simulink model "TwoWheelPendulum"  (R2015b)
settings: Solver=ode45  StartTime=0.0  StopTime=200.0  RelTol=1e-3
PreLoadFcn:
  | UIPanel();
  | open_system('getLog.slx');
StartFcn:
  | set_param('getLog', 'SimulationCommand', 'start');
StopFcn:
  | set_param('getLog', 'SimulationCommand', 'stop');
  | execInit();
undefined symbols (not defined in the file or in its folder): CircleT, DiscIntNeverNeededParam, EnableCP, GD, GI, goBack, goBackP, goFor, goForP, goLeft, goLeftP, goRight, goRightP, goUTern, GP, hok_t0, hok_t1, hok_t2, hok_t3, hok_v1, hok_v2, LongR, LP, ProgramMode, ShortR, SPK_FREQ_RB, SPK_VOL, WD, WheelBase, WheelR, WI, WP, zengo_v
libraries: simulink x56, legoev3lib x18
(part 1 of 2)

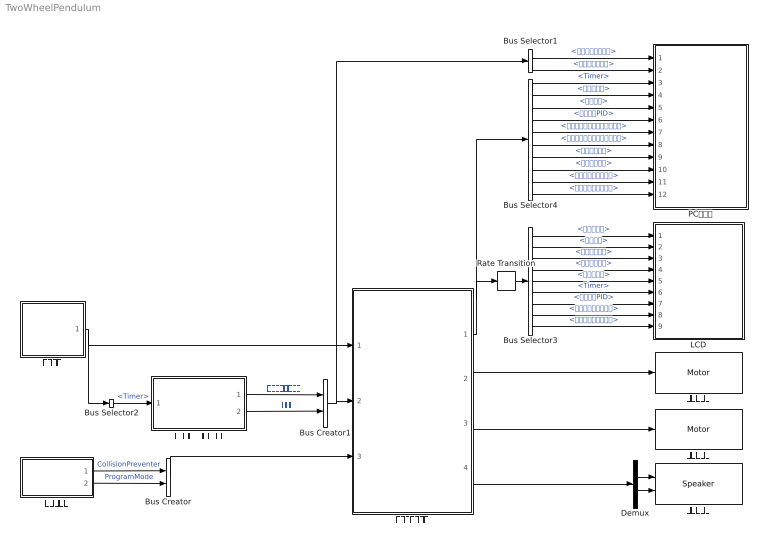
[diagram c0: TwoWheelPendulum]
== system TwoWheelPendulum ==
  Bus Creator : BusCreator  Inputs=2
  Bus Creator1 : BusCreator  Inputs=2
  Bus Selector1 : BusSelector  OutputSignals=直進加速度指示値,旋回速度指示値
  Bus Selector2 : BusSelector  OutputSignals=Timer
  Bus Selector3 : BusSelector  OutputSignals=車体角速度,車体角度,左車輪回転角,右車輪回転角,出力パワー,Timer,ジャイロPID,右コントローラ出力,左コントローラ出力
  Bus Selector4 : BusSelector  OutputSignals=Timer,車体角速度,車体角度,ジャイロPID,姿勢制御前右車輪角度指示値,姿勢制御前左車輪角度指示値,右車輪回転角,左車輪回転角,右コントローラ出力,左コントローラ出力
  Demux : Demux  Outputs=2
  LCD : Subsystem
  PCへ転送 : Subsystem  TreatAsAtomicUnit=on
  Rate Transition : RateTransition  OutPortSampleTime=0.1
  コントローラー : Subsystem
  スピーカー : legoev3lib/Speaker  sinputMode=Frequency and volume  sspeakerFreq=2600  sspeakerVolume=8  sspeakerDuration=1000
  センサー : Subsystem
  ユーザーコマンド入力 : Subsystem
  動作モード : Subsystem  TreatAsAtomicUnit=on
  右モーター : legoev3lib/Motor  sportNumber=A  sstopAction=Brake
  左モーター : legoev3lib/Motor  sportNumber=D  sstopAction=Brake
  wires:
  コントローラー/3(左車輪角度指示値) -> 左モーター/1
  コントローラー/2(右車輪角度指示値) -> 右モーター/1
  センサー/1(ロボットからの信号) -> Bus Selector2/1, コントローラー/1(ロボットからの信号)
  Bus Creator/1 -> コントローラー/3(モード設定)
  コントローラー/1(LCD表示信号) -> Bus Selector4/1, Rate Transition/1
  Bus Creator1/1 -> Bus Selector1/1, コントローラー/2(ユーザー操作)
  動作モード/2(プログラム走行モード) -> Bus Creator/2  "ProgramMode"
  動作モード/1(衝突回避実施) -> Bus Creator/1  "CollisionPreventer"
  ユーザーコマンド入力/1(直進加速度指示値) -> Bus Creator1/1  "直進加速度指示値"
  ユーザーコマンド入力/2(旋回速度指示値) -> Bus Creator1/2  "旋回速度指示値"
  Bus Selector2/1 -> ユーザーコマンド入力/1(Timer)  "<Timer>"
  コントローラー/4(スピーカー) -> Demux/1
  Demux/1 -> スピーカー/1
  Demux/2 -> スピーカー/2
  Bus Selector3/6 -> LCD/6(Line6：Timer xxxxx)  "<Timer>"
  Bus Selector3/7 -> LCD/7(Line7：GyroPID xxxxx)  "<ジャイロPID>"
  Bus Selector3/8 -> LCD/8(Line8：ControlR xxxxx)  "<右コントローラ出力>"
  Bus Selector3/5 -> LCD/5(Line5：Power xxxxx)  "<出力パワー>"
  Bus Selector3/4 -> LCD/4(Line4：WheelLT xxxxx)  "<右車輪回転角>"
  Bus Selector3/3 -> LCD/3(Line3：WheelRT xxxxx)  "<左車輪回転角>"
  Bus Selector3/2 -> LCD/2(Line2：Theta xxxxx)  "<車体角度>"
  Bus Selector3/1 -> LCD/1(Line1：Gyro xxxxx)  "<車体角速度>"
  Rate Transition/1 -> Bus Selector3/1
  Bus Selector3/9 -> LCD/9(Line9：ControlL xxxxx)  "<左コントローラ出力>"
  Bus Selector1/1 -> PCへ転送/1(前後指示)  "<直進加速度指示値>"
  Bus Selector1/2 -> PCへ転送/2(左右指示)  "<旋回速度指示値>"
  Bus Selector4/1 -> PCへ転送/3(time)  "<Timer>"
  Bus Selector4/2 -> PCへ転送/4(車体角速度)  "<車体角速度>"
  Bus Selector4/3 -> PCへ転送/5(車輪角度)  "<車体角度>"
  Bus Selector4/4 -> PCへ転送/6(ジャイロPID)  "<ジャイロPID>"
  Bus Selector4/5 -> PCへ転送/7(右車輪角度支持値)  "<姿勢制御前右車輪角度指示値>"
  Bus Selector4/6 -> PCへ転送/8("左車輪角度支持値 ")  "<姿勢制御前左車輪角度指示値>"
  Bus Selector4/8 -> PCへ転送/10(左車輪回転角)  "<左車輪回転角>"
  Bus Selector4/7 -> PCへ転送/9(右車輪回転角)  "<右車輪回転角>"
  Bus Selector4/9 -> PCへ転送/11(右コントローラー出力)  "<右コントローラ出力>"
  Bus Selector4/10 -> PCへ転送/12(左コントローラー出力)  "<左コントローラ出力>"

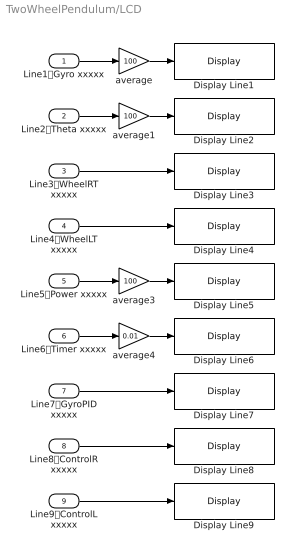
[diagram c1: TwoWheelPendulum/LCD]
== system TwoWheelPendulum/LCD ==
  Line1：Gyro xxxxx : Inport
  Line2：Theta xxxxx : Inport  Port=2
  Line3：WheelRT xxxxx : Inport  Port=3
  Line4：WheelLT xxxxx : Inport  Port=4
  Line5：Power xxxxx : Inport  Port=5
  Line6：Timer xxxxx : Inport  Port=6
  Line7：GyroPID xxxxx : Inport  Port=7
  Line8：ControlR xxxxx : Inport  Port=8
  Line9：ControlL xxxxx : Inport  Port=9
  Display Line1 : legoev3lib/Display  slcdStr=Gyro  slcdLine=1  slcdFormat=Decimal
  Display Line2 : legoev3lib/Display  slcdStr=Theta  slcdLine=2  slcdFormat=Decimal
  Display Line3 : legoev3lib/Display  slcdStr=WheelRT  slcdLine=3  slcdFormat=Decimal
  Display Line4 : legoev3lib/Display  slcdStr=WheelLT  slcdLine=4  slcdFormat=Decimal
  Display Line5 : legoev3lib/Display  slcdStr=Power  slcdLine=5  slcdFormat=Decimal
  Display Line6 : legoev3lib/Display  slcdStr=Timer  slcdLine=6  slcdFormat=Decimal
  Display Line7 : legoev3lib/Display  slcdStr=GuroPID  slcdLine=7  slcdFormat=Decimal
  Display Line8 : legoev3lib/Display  slcdStr=ControlR  slcdLine=8  slcdFormat=Decimal
  Display Line9 : legoev3lib/Display  slcdStr=ControlL  slcdLine=9  slcdFormat=Decimal
  average : Gain  Gain=100  ParamDataTypeStr=double
  average1 : Gain  Gain=100  ParamDataTypeStr=double
  average3 : Gain  Gain=100  ParamDataTypeStr=double
  average4 : Gain  Gain=0.01  ParamDataTypeStr=double
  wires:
  Line1：Gyro xxxxx/1 -> average/1
  Line2：Theta xxxxx/1 -> average1/1
  Line3：WheelRT xxxxx/1 -> Display Line3/1
  Line5：Power xxxxx/1 -> average3/1
  average/1 -> Display Line1/1
  average1/1 -> Display Line2/1
  Line4：WheelLT xxxxx/1 -> Display Line4/1
  average3/1 -> Display Line5/1
  Line8：ControlR xxxxx/1 -> Display Line8/1
  Line9：ControlL xxxxx/1 -> Display Line9/1
  average4/1 -> Display Line6/1
  Line6：Timer xxxxx/1 -> average4/1
  Line7：GyroPID xxxxx/1 -> Display Line7/1

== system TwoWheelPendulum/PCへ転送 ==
  前後指示 : Inport
  左右指示 : Inport  Port=2
  time : Inport  Port=3
  車体角速度 : Inport  Port=4
  車輪角度 : Inport  Port=5
  ジャイロPID : Inport  Port=6
  右車輪角度支持値 : Inport  Port=7
  "左車輪角度支持値 " : Inport  Port=8
  右車輪回転角 : Inport  Port=9
  左車輪回転角 : Inport  Port=10
  右コントローラー出力 : Inport  Port=11
  左コントローラー出力 : Inport  Port=12
  Scope : Scope  NumInputPorts=12
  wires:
  time/1 -> Scope/3
  車体角速度/1 -> Scope/4
  車輪角度/1 -> Scope/5
  ジャイロPID/1 -> Scope/6
  右車輪角度支持値/1 -> Scope/7
  前後指示/1 -> Scope/1
  左右指示/1 -> Scope/2
  "左車輪角度支持値 "/1 -> Scope/8
  右車輪回転角/1 -> Scope/9
  左車輪回転角/1 -> Scope/10
  右コントローラー出力/1 -> Scope/11
  左コントローラー出力/1 -> Scope/12

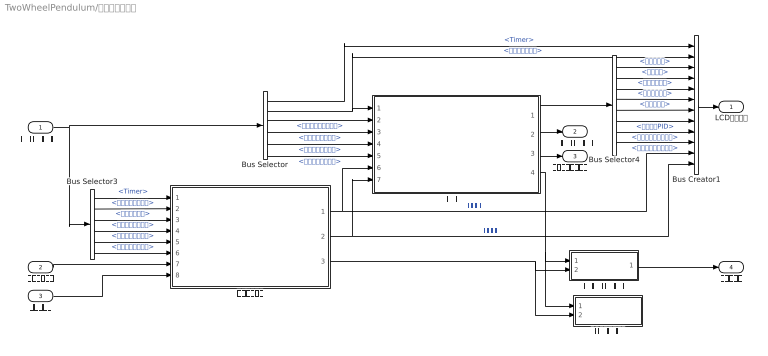
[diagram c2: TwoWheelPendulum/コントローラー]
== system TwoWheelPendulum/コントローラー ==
  ロボットからの信号 : Inport
  ユーザー操作 : Inport  Port=2
  モード設定 : Inport  Port=3
  Bus Creator1 : BusCreator  Inputs=12
  Bus Selector : BusSelector  OutputSignals=Timer,バッテリー残量,ジャイロセンサー値,右モーター回転角,左モーター回転角,リセットボタン値
  Bus Selector3 : BusSelector  OutputSignals=Timer,超音波センサー値,光センサー値,リセットボタン値,右モーター回転角,左モーター回転角
  Bus Selector4 : BusSelector  OutputSignals=車体角速度,車体角度,左車輪回転角,右車輪回転角,出力パワー,ジャイロPID,右コントローラ出力,左コントローラ出力
  サウンドセレクター : Subsystem
  ロボット操作 : Subsystem
  姿勢制御 : Subsystem
  特殊制御有効判定 : Subsystem
  LCD表示信号 : Outport
  右車輪角度指示値 : Outport  Port=2
  左車輪角度指示値 : Outport  Port=3
  スピーカー : Outport  Port=4
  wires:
  ロボットからの信号/1 -> Bus Selector3/1, Bus Selector/1
  Bus Selector/2 -> Bus Creator1/2, 姿勢制御/1(バッテリー値)  "<バッテリー残量>"
  Bus Selector3/2 -> ロボット操作/2(超音波センサー値)  "<超音波センサー値>"
  Bus Selector3/3 -> ロボット操作/3(光センサー値)  "<光センサー値>"
  Bus Creator1/1 -> LCD表示信号/1
  ユーザー操作/1 -> ロボット操作/7(ユーザー操作)
  モード設定/1 -> ロボット操作/8(モード設定)
  Bus Selector3/4 -> ロボット操作/4(Reset)  "<リセットボタン値>"
  Bus Selector/3 -> 姿勢制御/2(ジャイロ値)  "<ジャイロセンサー値>"
  Bus Selector/4 -> 姿勢制御/3(右車輪回転角)  "<右モーター回転角>"
  Bus Selector/5 -> 姿勢制御/4(左車輪回転角)  "<左モーター回転角>"
  Bus Selector/6 -> 姿勢制御/5(リセット)  "<リセットボタン値>"
  ロボット操作/1(姿勢制御前右車輪角度指示値) -> Bus Creator1/11, 姿勢制御/6(姿勢制御前右車輪角度指示値)  "姿勢制御前右車輪角度指示値"
  姿勢制御/2(右車輪角度指示値) -> 右車輪角度指示値/1
  姿勢制御/3(左車輪角度指示値) -> 左車輪角度指示値/1
  姿勢制御/1(LCD表示信号) -> Bus Selector4/1
  Bus Selector4/1 -> Bus Creator1/3  "<車体角速度>"
  Bus Selector4/2 -> Bus Creator1/4  "<車体角度>"
  Bus Selector4/3 -> Bus Creator1/5  "<左車輪回転角>"
  Bus Selector4/4 -> Bus Creator1/6  "<右車輪回転角>"
  Bus Selector4/5 -> Bus Creator1/7  "<出力パワー>"
  Bus Selector4/6 -> Bus Creator1/8  "<ジャイロPID>"
  Bus Selector4/7 -> Bus Creator1/9  "<右コントローラ出力>"
  Bus Selector4/8 -> Bus Creator1/10  "<左コントローラ出力>"
  ロボット操作/2(姿勢制御前左車輪角度指示値) -> Bus Creator1/12, 姿勢制御/7(姿勢制御前左車輪角度指示値)  "姿勢制御前左車輪角度指示値"
  Bus Selector/1 -> Bus Creator1/1  "<Timer>"
  Bus Selector3/1 -> ロボット操作/1(Timer)  "<Timer>"
  Bus Selector3/5 -> ロボット操作/5(右車輪回転角)  "<右モーター回転角>"
  Bus Selector3/6 -> ロボット操作/6(左車輪回転角)  "<左モーター回転角>"
  サウンドセレクター/1(スピーカー) -> スピーカー/1
  姿勢制御/4(スピーカー) -> 特殊制御有効判定/1(ルール制御), サウンドセレクター/1(優先度2)
  ロボット操作/3(スピーカー) -> 特殊制御有効判定/2(衝突防止), サウンドセレクター/2(優先度1)

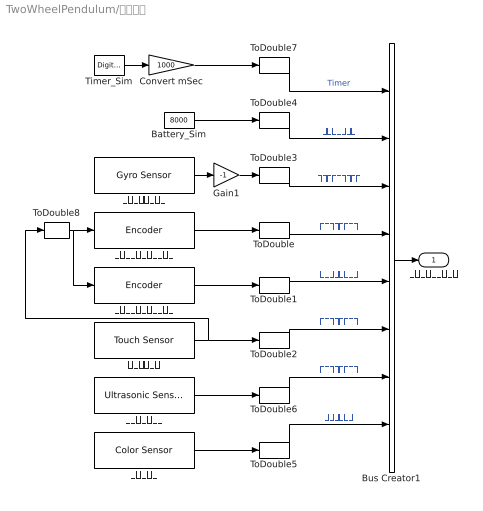
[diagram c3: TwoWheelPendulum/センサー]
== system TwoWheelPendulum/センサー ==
  Battery_Sim : Constant  Value=8000
  Bus Creator1 : BusCreator  Inputs=8
  Convert mSec : Gain  Gain=1000
  Gain1 : Gain  Gain=-1
  Timer_Sim : DigitalClock  SampleTime=0.1
  ToDouble{,1,3,5..7} (6 alike) : DataTypeConversion  OutDataTypeStr=double
  ToDouble2 : DataTypeConversion  OutMin=0  OutMax=1  OutDataTypeStr=double
  ToDouble4 : DataTypeConversion  OutMin=0  OutMax=9000  OutDataTypeStr=double
  ToDouble8 : DataTypeConversion  OutMin=0  OutMax=1  OutDataTypeStr=int8
  ジャイロセンサー : legoev3lib/Gyro Sensor  portNumber=3  sampleTime=0.01
  タッチボタン : legoev3lib/Touch Sensor  portNumber=4  sampleTime=0.1
  光センサー : legoev3lib/Color Sensor  portNumber=1  mode=Reflected light intensity  sampleTime=0.1
  右モーターエンコーダー : legoev3lib/Encoder  portNumber=A  opMode=Reset by external signal  sampleTime=0.01
  左モーターエンコーダー : legoev3lib/Encoder  portNumber=D  opMode=Reset by external signal  sampleTime=0.01
  超音波センサー : legoev3lib/Ultrasonic Sensor  PortNumber=2  sampleTime=0.1
  ロボットからの信号 : Outport
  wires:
  ToDouble1/1 -> Bus Creator1/5  "左モーター回転角"
  Bus Creator1/1 -> ロボットからの信号/1
  ToDouble7/1 -> Bus Creator1/1  "Timer"
  ToDouble4/1 -> Bus Creator1/2  "バッテリー残量"
  ToDouble3/1 -> Bus Creator1/3  "ジャイロセンサー値"
  ToDouble/1 -> Bus Creator1/4  "右モーター回転角"
  ToDouble2/1 -> Bus Creator1/6  "リセットボタン値"
  ToDouble6/1 -> Bus Creator1/7  "超音波センサー値"
  ToDouble5/1 -> Bus Creator1/8  "光センサー値"
  Timer_Sim/1 -> Convert mSec/1
  Battery_Sim/1 -> ToDouble4/1
  ジャイロセンサー/1 -> Gain1/1
  右モーターエンコーダー/1 -> ToDouble/1
  左モーターエンコーダー/1 -> ToDouble1/1
  超音波センサー/1 -> ToDouble6/1
  光センサー/1 -> ToDouble5/1
  ToDouble8/1 -> 左モーターエンコーダー/1, 右モーターエンコーダー/1
  Gain1/1 -> ToDouble3/1
  Convert mSec/1 -> ToDouble7/1
  タッチボタン/1 -> ToDouble2/1, ToDouble8/1

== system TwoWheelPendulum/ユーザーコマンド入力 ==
  Timer : Inport
  Dead Zone : DeadZone  LowerValue=-0.0002  UpperValue=0.0002
  Discrete Filter : DiscreteFilter  Numerator=[0.4]  Denominator=[1 -0.6]
  Gain : Gain  Gain=0.15
  Manual Switch : ManualSwitch
  PADコマンド入力 : Subsystem  TreatAsAtomicUnit=on  SystemSampleTime=0.1
  Switch : Switch  Criteria=u2 ~= 0
  Switch1 : Switch  Criteria=u2 ~= 0
  UIコマンド入力 : Subsystem  TreatAsAtomicUnit=on  SystemSampleTime=0.1
  直進加速度指示値 : Outport
  旋回速度指示値 : Outport  Port=2
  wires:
  Timer/1 -> UIコマンド入力/1(Timer)
  PADコマンド入力/1("Turn\t") -> Switch/2, Switch/1
  PADコマンド入力/2(Straight) -> Switch1/2, Switch1/1
  UIコマンド入力/2(Straight) -> Switch1/3
  UIコマンド入力/1("Turn\t") -> Switch/3
  Switch/1 -> 旋回速度指示値/1  "Turn"
  Switch1/1 -> Gain/1
  Dead Zone/1 -> Manual Switch/2  "Straight"
  Discrete Filter/1 -> Dead Zone/1
  Gain/1 -> Discrete Filter/1, Manual Switch/1
  Manual Switch/1 -> 直進加速度指示値/1

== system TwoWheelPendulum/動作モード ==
  Constant2 : Constant  Value=EnableCP
  Constant3 : Constant  Value=ProgramMode
  衝突回避実施 : Outport
  プログラム走行モード : Outport  Port=2
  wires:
  Constant2/1 -> 衝突回避実施/1
  Constant3/1 -> プログラム走行モード/1

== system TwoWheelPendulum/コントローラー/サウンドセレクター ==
  優先度2 : Inport
  優先度1 : Inport  Port=2
  Demux : Demux  Outputs=2
  Switch : Switch  Criteria=u2 > Threshold
  Terminator : Terminator
  スピーカー : Outport
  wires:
  優先度1/1 -> Switch/1, Demux/1
  Demux/1 -> Terminator/1
  Demux/2 -> Switch/2
  Switch/1 -> スピーカー/1
  優先度2/1 -> Switch/3

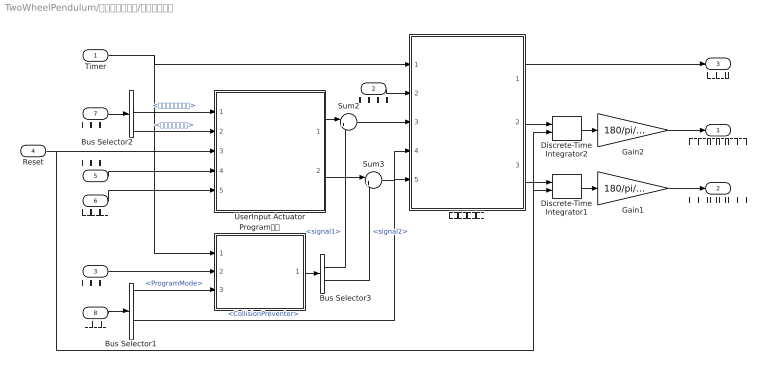
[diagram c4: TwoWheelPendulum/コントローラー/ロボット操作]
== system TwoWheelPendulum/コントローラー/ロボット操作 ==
  Timer : Inport
  超音波センサー値 : Inport  Port=2
  光センサー値 : Inport  Port=3
  Reset : Inport  Port=4
  右車輪回転角 : Inport  Port=5
  左車輪回転角 : Inport  Port=6
  ユーザー操作 : Inport  Port=7
  モード設定 : Inport  Port=8
  Bus Selector1 : BusSelector  OutputSignals=ProgramMode,CollisionPreventer
  Bus Selector2 : BusSelector  OutputSignals=直進加速度指示値,旋回速度指示値
  Bus Selector3 : BusSelector  OutputSignals=signal1,signal2
  Discrete-Time Integrator1 : DiscreteIntegrator  ExternalReset=rising  InitialConditionSetting=State (most efficient)  SampleTime=-1  UpperSaturationLimit=2000  LowerSaturationLimit=-2000  ICPrevOutput=DiscIntNeverNeededParam  ICPrevScaledInput=DiscIntNeverNeededParam
  Discrete-Time Integrator2 : DiscreteIntegrator  ExternalReset=rising  InitialConditionSetting=State (most efficient)  SampleTime=-1  UpperSaturationLimit=2000  LowerSaturationLimit=-2000  ICPrevOutput=DiscIntNeverNeededParam  ICPrevScaledInput=DiscIntNeverNeededParam
  Gain1 : Gain  Gain=180/pi/WheelR
  Gain2 : Gain  Gain=180/pi/WheelR
  Program動作 : Subsystem
  Sum2 : Sum  Inputs=|++
  Sum3 : Sum  Inputs=|++
  UserInput Actuator : Subsystem
  衝突防止システム : Subsystem
  姿勢制御前右車輪角度指示値 : Outport
  姿勢制御前左車輪角度指示値 : Outport  Port=2
  スピーカー : Outport  Port=3
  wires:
  Discrete-Time Integrator2/1 -> Gain2/1
  Discrete-Time Integrator1/1 -> Gain1/1
  モード設定/1 -> Bus Selector1/1
  ユーザー操作/1 -> Bus Selector2/1
  Bus Selector2/1 -> UserInput Actuator/1(直進)  "<直進加速度指示値>"
  Reset/1 -> Discrete-Time Integrator2/2, Discrete-Time Integrator1/2, UserInput Actuator/3(Reset)
  Bus Selector1/1 -> Program動作/3(Mode)  "<ProgramMode>"
  Bus Selector2/2 -> UserInput Actuator/2(旋回)  "<旋回速度指示値>"
  Gain2/1 -> 姿勢制御前右車輪角度指示値/1
  Gain1/1 -> 姿勢制御前左車輪角度指示値/1
  UserInput Actuator/2(左車輪速度要求) -> Sum3/1
  UserInput Actuator/1(右車輪速度要求) -> Sum2/1
  右車輪回転角/1 -> UserInput Actuator/4(右車輪回転角)
  左車輪回転角/1 -> UserInput Actuator/5(左車輪回転角)
  Timer/1 -> Program動作/1(Timer), 衝突防止システム/1(Timer)
  超音波センサー値/1 -> 衝突防止システム/2(超音波センサー値)
  Sum2/1 -> 衝突防止システム/3(右抑制前速度要求)
  Sum3/1 -> 衝突防止システム/4(左抑制前速度要求)
  Bus Selector1/2 -> 衝突防止システム/5(enableCP)  "<CollisionPreventer>"
  衝突防止システム/1(Vol_Freq) -> スピーカー/1
  衝突防止システム/2(右側速度要求) -> Discrete-Time Integrator2/1
  衝突防止システム/3(左側速度要求) -> Discrete-Time Integrator1/1
  Bus Selector3/2 -> Sum3/2  "<signal2>"
  Bus Selector3/1 -> Sum2/2  "<signal1>"
  Program動作/1(速度要求) -> Bus Selector3/1
  光センサー値/1 -> Program動作/2(Light)

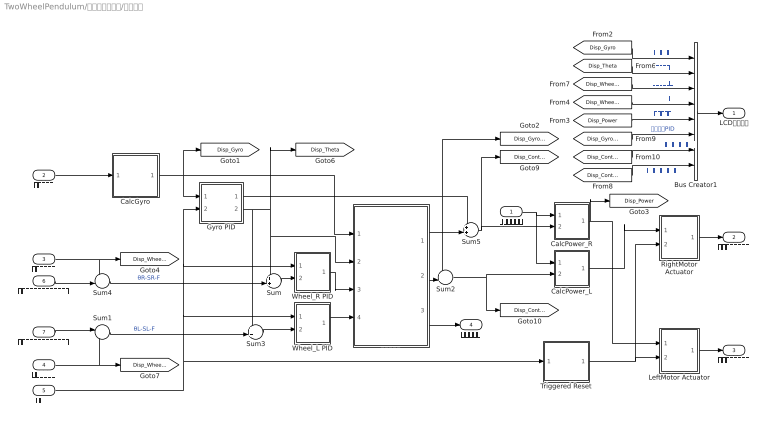
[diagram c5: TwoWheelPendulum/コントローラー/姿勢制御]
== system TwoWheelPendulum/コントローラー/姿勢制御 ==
  バッテリー値 : Inport
  ジャイロ値 : Inport  Port=2
  右車輪回転角 : Inport  Port=3
  左車輪回転角 : Inport  Port=4
  リセット : Inport  Port=5
  姿勢制御前右車輪角度指示値 : Inport  Port=6
  姿勢制御前左車輪角度指示値 : Inport  Port=7
  Bus Creator1 : BusCreator  Inputs=8
  CalcGyro : Subsystem
  CalcPower_L : Subsystem
  CalcPower_R : Subsystem
  Gyro PID : Subsystem
  LeftMotor Actuator : Subsystem
  RightMotor Actuator : Subsystem
  Sum{,2..3,5} (4 alike) : Sum  Inputs=++|
  Sum1 : Sum  Inputs=|-+
  Sum4 : Sum  Inputs=+-|
  Triggered Reset : Subsystem
  Wheel_L PID : Subsystem
  Wheel_R PID : Subsystem
  ルール制御 : Subsystem
  LCD表示信号 : Outport
  右車輪角度指示値 : Outport  Port=2
  左車輪角度指示値 : Outport  Port=3
  スピーカー : Outport  Port=4
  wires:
  バッテリー値/1 -> CalcPower_L/1(Bat), CalcPower_R/1(Bat)
  ルール制御/2(左補正値) -> Sum2/2
  ルール制御/1(右補正値) -> Sum5/2
  Sum/1 -> Wheel_R PID/2(Ang)
  RightMotor Actuator/1(Pow) -> 右車輪角度指示値/1
  LeftMotor Actuator/1(Pow) -> 左車輪角度指示値/1
  Triggered Reset/1(Trigger) -> RightMotor Actuator/2(Reset), LeftMotor Actuator/2(Reset)
  ジャイロ値/1 -> CalcGyro/1(Gyro)
  Sum5/1 -> [Disp_ControlR], CalcPower_R/2(Req)
  [Disp_ControlL] -> Bus Creator1/8  "左コントローラ出力"
  [Disp_Gyro] -> Bus Creator1/1  "車体角速度"
  [Disp_Power] -> Bus Creator1/5  "出力パワー"
  [Disp_WheelRT] -> Bus Creator1/4  "右車輪回転角"
  [Disp_Theta] -> Bus Creator1/2  "車体角度"
  [Disp_WheelLT] -> Bus Creator1/3  "左車輪回転角"
  Bus Creator1/1 -> LCD表示信号/1
  [Disp_GyroPID] -> Bus Creator1/6  "ジャイロPID"
  [Disp_ControlR] -> Bus Creator1/7  "右コントローラ出力"
  リセット/1 -> Gyro PID/2(Reset), Wheel_R PID/1(Reset), Wheel_L PID/1(Reset), Triggered Reset/1(Reset)
  CalcGyro/1(GyroD) -> ルール制御/1(角速度), [Disp_Gyro], Gyro PID/1(GyroD)
  Gyro PID/1(Req) -> Sum2/1, Sum5/1, [Disp_GyroPID]
  Gyro PID/2(Theta) -> Sum3/1, ルール制御/2(角度), Sum/1, [Disp_Theta]
  Sum1/1 -> Sum3/2  "θL-SL-F"
  姿勢制御前右車輪角度指示値/1 -> Sum4/2
  右車輪回転角/1 -> Sum4/1, [Disp_WheelRT]
  左車輪回転角/1 -> [Disp_WheelLT], Sum1/2
  Sum4/1 -> Sum/2  "θR-SR-F"
  CalcPower_R/1(Pow) -> [Disp_Power], LeftMotor Actuator/1(Req)
  CalcPower_L/1(Pow) -> RightMotor Actuator/1(Req)
  姿勢制御前左車輪角度指示値/1 -> Sum1/1
  Sum2/1 -> [Disp_ControlL], CalcPower_L/2(Req)
  Sum3/1 -> Wheel_L PID/2(Ang)
  Wheel_L PID/1(Req) -> ルール制御/4(左要求値)
  Wheel_R PID/1(Req) -> ルール制御/3(右要求値)
  ルール制御/3(スピーカー) -> スピーカー/1

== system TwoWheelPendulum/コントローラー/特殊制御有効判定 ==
  ルール制御 : Inport
  衝突防止 : Inport  Port=2
  Compare To Zero : simulink/Logic and Bit Operations/Compare To Zero  relop=>  OutDataTypeStr=boolean
  Compare To Zero1 : simulink/Logic and Bit Operations/Compare To Zero  relop=>  OutDataTypeStr=boolean
  Demux : Demux  Outputs=2
  Demux1 : Demux  Outputs=2
  Terminator : Terminator
  Terminator1 : Terminator
  判定信号 : Scope  NumInputPorts=2
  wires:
  ルール制御/1 -> Demux/1
  Demux/1 -> Terminator/1
  Demux/2 -> Compare To Zero1/1
  衝突防止/1 -> Demux1/1
  Demux1/1 -> Terminator1/1
  Demux1/2 -> Compare To Zero/1
  Compare To Zero1/1 -> 判定信号/1  "ルール制御"
  Compare To Zero/1 -> 判定信号/2  "衝突防止"

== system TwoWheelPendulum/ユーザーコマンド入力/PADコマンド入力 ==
  Constant1 : Constant  Value=goForP
  Constant2 : Constant  Value=goBackP
  Constant3 : Constant  Value=goLeftP
  Constant4 : Constant  Value=goRightP
  Sum3 : Sum  Inputs=|+-
  Sum6 : Sum  Inputs=|-+
  ToDouble{1..4} (4 alike) : DataTypeConversion  OutDataTypeStr=double
  "Turn\t" : Outport
  Straight : Outport  Port=2
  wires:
  Sum6/1 -> "Turn\t"/1
  ToDouble1/1 -> Sum6/2
  ToDouble2/1 -> Sum3/1
  ToDouble3/1 -> Sum3/2
  Constant4/1 -> ToDouble4/1
  Constant3/1 -> ToDouble1/1
  Constant2/1 -> ToDouble3/1
  Constant1/1 -> ToDouble2/1
  ToDouble4/1 -> Sum6/1
  Sum3/1 -> Straight/1

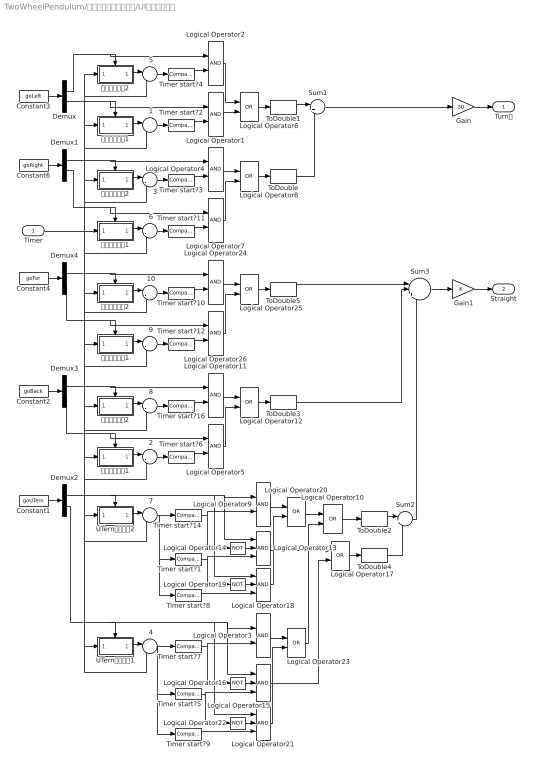
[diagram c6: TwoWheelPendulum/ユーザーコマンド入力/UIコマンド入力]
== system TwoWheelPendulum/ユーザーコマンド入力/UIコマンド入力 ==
  Timer : Inport
   {1..10} (10 alike) : Sum  Inputs=|-+
  Constant1 : Constant  Value=goUTern
  Constant2 : Constant  Value=goBack
  Constant3 : Constant  Value=goLeft
  Constant4 : Constant  Value=goFor
  Constant6 : Constant  Value=goRight
  Demux{,1..4} (5 alike) : Demux  Outputs=2
  Gain : Gain  Gain=30
  Gain1 : Gain
  Logical Operator{1..5,7,9,11,24,26} (10 alike) : Logic  IconShape=distinctive  AllPortsSameDT=off  OutDataTypeStr=boolean
  Logical Operator{6,8,10,12,17,20,23,25} (8 alike) : Logic  Operator=OR  IconShape=distinctive  AllPortsSameDT=off  OutDataTypeStr=boolean
  Logical Operator{13,15,18,21} (4 alike) : Logic  Inputs=3  IconShape=distinctive  AllPortsSameDT=off  OutDataTypeStr=boolean
  Logical Operator{14,16,19,22} (4 alike) : Logic  Operator=NOT  IconShape=distinctive  AllPortsSameDT=off  OutDataTypeStr=boolean
  Sum1 : Sum  Inputs=|+-
  Sum2 : Sum  Inputs=|+-
  Sum3 : Sum  Inputs=||+-+
  Timer start?1 : simulink/Logic and Bit Operations/Compare To Constant  relop=<  const=9000  OutDataTypeStr=boolean
  Timer start?{6,10,12,16} (4 alike) : simulink/Logic and Bit Operations/Compare To Constant  relop=<  const=800  OutDataTypeStr=boolean
  Timer start?{2..4,11} (4 alike) : simulink/Logic and Bit Operations/Compare To Constant  relop=<  const=350  OutDataTypeStr=boolean
  Timer start?14 : simulink/Logic and Bit Operations/Compare To Constant  relop=<  const=3000  OutDataTypeStr=boolean
  Timer start?5 : simulink/Logic and Bit Operations/Compare To Constant  relop=<  const=9000  OutDataTypeStr=boolean
  Timer start?7 : simulink/Logic and Bit Operations/Compare To Constant  relop=<  const=3000  OutDataTypeStr=boolean
  Timer start?8 : simulink/Logic and Bit Operations/Compare To Constant  relop=<  const=12000  OutDataTypeStr=boolean
  Timer start?9 : simulink/Logic and Bit Operations/Compare To Constant  relop=<  const=12000  OutDataTypeStr=boolean
  ToDouble{,1..5} (6 alike) : DataTypeConversion  OutDataTypeStr=double
  UTernトリガー1 : Subsystem  TreatAsAtomicUnit=on
  UTernトリガー2 : Subsystem  TreatAsAtomicUnit=on
  前進トリガー1 : Subsystem  TreatAsAtomicUnit=on
  前進トリガー2 : Subsystem  TreatAsAtomicUnit=on
  右折トリガー1 : Subsystem  TreatAsAtomicUnit=on
  右折トリガー2 : Subsystem  TreatAsAtomicUnit=on
  左折トリガー1 : Subsystem  TreatAsAtomicUnit=on
  左折トリガー2 : Subsystem  TreatAsAtomicUnit=on
  後退トリガー1 : Subsystem  TreatAsAtomicUnit=on
  後退トリガー2 : Subsystem  TreatAsAtomicUnit=on
  "Turn\t" : Outport
  Straight : Outport  Port=2
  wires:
  " 1"/1 -> Timer start?2/1
  Sum1/1 -> Gain/1
  Timer start?2/1 -> Logical Operator1/2
  ToDouble1/1 -> Sum1/1
  Sum2/1 -> Sum3/3
  ToDouble3/1 -> Sum3/2
  左折トリガー1/1(Out1) -> " 1"/1
  Sum3/1 -> Gain1/1
  Demux3/2 -> Logical Operator5/1, 後退トリガー1/Trigger
  Logical Operator1/1 -> Logical Operator6/2
  " 3"/1 -> Timer start?3/1
  Timer start?3/1 -> Logical Operator4/2
  ToDouble/1 -> Sum1/2
  右折トリガー2/1(Out1) -> " 3"/1
  Logical Operator4/1 -> Logical Operator8/1
  Demux/2 -> Logical Operator1/1, 左折トリガー1/Trigger
  Demux1/1 -> Logical Operator4/1, 右折トリガー2/Trigger
  " 2"/1 -> Timer start?6/1
  Timer start?6/1 -> Logical Operator5/2
  後退トリガー1/1(Out1) -> " 2"/1
  Logical Operator5/1 -> Logical Operator12/2
  " 4"/1 -> Timer start?9/1, Timer start?5/1, Timer start?7/1
  UTernトリガー1/1(Out1) -> " 4"/1
  Logical Operator23/1 -> Logical Operator10/2
  Gain/1 -> "Turn\t"/1
  Gain1/1 -> Straight/1
  " 5"/1 -> Timer start?4/1
  Timer start?4/1 -> Logical Operator2/2
  左折トリガー2/1(Out1) -> " 5"/1
  Demux/1 -> Logical Operator2/1, 左折トリガー2/Trigger
  Logical Operator2/1 -> Logical Operator6/1
  Logical Operator6/1 -> ToDouble1/1
  " 6"/1 -> Timer start?11/1
  Timer start?11/1 -> Logical Operator7/2
  右折トリガー1/1(Out1) -> " 6"/1
  Demux1/2 -> Logical Operator7/1, 右折トリガー1/Trigger
  Logical Operator7/1 -> Logical Operator8/2
  Logical Operator8/1 -> ToDouble/1
  Demux2/1 -> UTernトリガー2/Trigger, Logical Operator18/1, Logical Operator13/1, Logical Operator9/1
  " 7"/1 -> Timer start?8/1, Timer start?1/1, Timer start?14/1
  Timer start?14/1 -> Logical Operator14/1, Logical Operator9/2
  UTernトリガー2/1(Out1) -> " 7"/1
  Logical Operator9/1 -> Logical Operator20/1
  Logical Operator10/1 -> ToDouble2/1
  Demux3/1 -> Logical Operator11/1, 後退トリガー2/Trigger
  " 8"/1 -> Timer start?16/1
  Timer start?16/1 -> Logical Operator11/2
  後退トリガー2/1(Out1) -> " 8"/1
  Timer/1 -> " 10"/2, 前進トリガー1/1(In1), " 9"/2, " 4"/2, UTernトリガー1/1(In1), " 7"/2, UTernトリガー2/1(In1), " 2"/2, 後退トリガー1/1(In1), " 8"/2, 後退トリガー2/1(In1), 前進トリガー2/1(In1), " 6"/2, 左折トリガー2/1(In1), " 5"/2, 左折トリガー1/1(In1), " 1"/2, 右折トリガー2/1(In1), " 3"/2, 右折トリガー1/1(In1)
  Logical Operator11/1 -> Logical Operator12/1
  Logical Operator12/1 -> ToDouble3/1
  Constant3/1 -> Demux/1
  Constant6/1 -> Demux1/1
  Constant1/1 -> Demux2/1
  Constant2/1 -> Demux3/1
  Logical Operator14/1 -> Logical Operator13/2
  Timer start?1/1 -> Logical Operator19/1, Logical Operator13/3
  Timer start?7/1 -> Logical Operator16/1, Logical Operator3/2
  Logical Operator16/1 -> Logical Operator15/2
  Logical Operator15/1 -> Logical Operator17/2
  Logical Operator13/1 -> Logical Operator17/1
  Logical Operator17/1 -> ToDouble4/1
  ToDouble2/1 -> Sum2/1
  ToDouble4/1 -> Sum2/2
  Timer start?8/1 -> Logical Operator18/3
  Logical Operator19/1 -> Logical Operator18/2
  Logical Operator18/1 -> Logical Operator20/2
  Logical Operator20/1 -> Logical Operator10/1
  Demux2/2 -> UTernトリガー1/Trigger, Logical Operator21/1, Logical Operator15/1, Logical Operator3/1
  Timer start?5/1 -> Logical Operator22/1, Logical Operator15/3
  Timer start?9/1 -> Logical Operator21/3
  Logical Operator22/1 -> Logical Operator21/2
  Logical Operator3/1 -> Logical Operator23/1
  Logical Operator21/1 -> Logical Operator23/2
  ToDouble5/1 -> Sum3/1
  Demux4/2 -> Logical Operator26/1, 前進トリガー1/Trigger
  " 9"/1 -> Timer start?12/1
  Timer start?12/1 -> Logical Operator26/2
  前進トリガー1/1(Out1) -> " 9"/1
  Logical Operator26/1 -> Logical Operator25/2
  Demux4/1 -> Logical Operator24/1, 前進トリガー2/Trigger
  " 10"/1 -> Timer start?10/1
  Timer start?10/1 -> Logical Operator24/2
  前進トリガー2/1(Out1) -> " 10"/1
  Logical Operator24/1 -> Logical Operator25/1
  Logical Operator25/1 -> ToDouble5/1
  Constant4/1 -> Demux4/1

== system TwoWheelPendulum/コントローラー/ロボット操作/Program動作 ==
  Timer : Inport
  Light : Inport  Port=2
  Mode : Inport  Port=3
  " 3" : Sum  Inputs=-+|
  Detect Change : simulink/Logic and Bit Operations/Detect Change  vinit=0  InputProcessing=Inherited  OutDataTypeStr=boolean
  Program Selector1 : MultiPortSwitch  DataPortOrder=Specify indices  Inputs=2  DataPortIndices={2,3,4,5,1}  DataPortForDefault=Additional data port  DiagnosticForDefault=None
  トリガー : Subsystem  TreatAsAtomicUnit=on
  ライントレース : Subsystem
  前後動作 : Subsystem
  方形動作 : Subsystem
  楕円操作 : Subsystem
  無動作 : Subsystem
  速度要求 : Outport
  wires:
  Program Selector1/1 -> 速度要求/1
  Mode/1 -> Detect Change/1, Program Selector1/1
  無動作/1(Out) -> Program Selector1/7, Program Selector1/6
  Light/1 -> ライントレース/1(Light)
  ライントレース/1(Out) -> Program Selector1/2
  方形動作/1(Out) -> Program Selector1/4
  " 3"/1 -> 前後動作/1(Timer), 方形動作/1(Timer), 楕円操作/1(Timer)
  楕円操作/1(Out) -> Program Selector1/5
  トリガー/1(Out) -> " 3"/1
  Timer/1 -> " 3"/2, トリガー/1(In)
  Detect Change/1 -> トリガー/Trigger
  前後動作/1(Out) -> Program Selector1/3

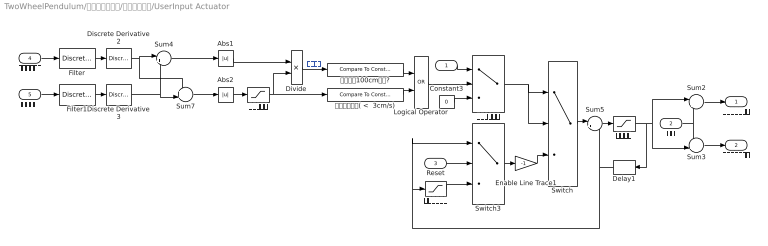
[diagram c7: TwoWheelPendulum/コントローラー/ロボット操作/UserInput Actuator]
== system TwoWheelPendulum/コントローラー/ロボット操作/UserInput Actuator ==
  直進 : Inport
  旋回 : Inport  Port=2
  Reset : Inport  Port=3
  右車輪回転角 : Inport  Port=4
  左車輪回転角 : Inport  Port=5
  Abs1 : Abs
  Abs2 : Abs
  Constant3 : Constant  Value=0
  Delay1 : Delay  DelayLength=1  InitialCondition=0
  Discrete Derivative2 : simulink/Discrete/Discrete Derivative  gainval=1.0  ICPrevScaledInput=0.0  InputProcessing=Inherited  OutMin=[]  OutMax=[]  OutDataType=fixdt(1, 16)  OutScaling=2^-10  DoSatur=off
  Discrete Derivative3 : simulink/Discrete/Discrete Derivative  gainval=1.0  ICPrevScaledInput=0.0  InputProcessing=Inherited  OutMin=[]  OutMax=[]  OutDataType=fixdt(1, 16)  OutScaling=2^-10  DoSatur=off
  Divide : Product  Inputs=*/
  Enable Line Trace1 : Gain  Gain=-1  OutDataTypeStr=double
  Filter : DiscreteFilter  Numerator=[0.02]  Denominator=[1 -0.98]
  Filter1 : DiscreteFilter  Numerator=[0.02]  Denominator=[1 -0.98]
  Logical Operator : Logic  Operator=OR  AllPortsSameDT=off  OutDataTypeStr=boolean
  Sum2 : Sum  Inputs=|++
  Sum3 : Sum  Inputs=-+|
  Sum4 : Sum  Inputs=|+-
  Sum5 : Sum  Inputs=|++
  Sum7 : Sum  Inputs=++|
  Switch : Switch  Criteria=u2 ~= 0
  Switch3 : Switch  Criteria=u2 ~= 0
  ゼロ割防止 : Saturate  UpperLimit=inf  LowerLimit=0.01
  旋回半径100cm以内? : simulink/Logic and Bit Operations/Compare To Constant  relop=<  const=0.5*WheelBase/100  OutDataTypeStr=boolean
  直進可否判定 : Switch  Criteria=u2 ~= 0  Threshold=0.5*WheelBase/100
  速度制限 : Saturate  UpperLimit=40  LowerLimit=-40
  速度減衰制限 : Saturate  UpperLimit=0.18  LowerLimit=-0.18
  静止している( <  3cm/s) : simulink/Logic and Bit Operations/Compare To Constant  relop=<  const=180/pi/WheelR*6  OutDataTypeStr=boolean
  右車輪速度要求 : Outport
  左車輪速度要求 : Outport  Port=2
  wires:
  直進可否判定/1 -> Switch/1, Switch/2
  Switch/1 -> Sum5/1
  速度減衰制限/1 -> Switch3/3
  Delay1/1 -> 速度減衰制限/1, Switch3/1, Sum5/2
  Reset/1 -> Switch3/2
  速度制限/1 -> Sum3/2, Sum2/1, Delay1/1
  Switch3/1 -> Enable Line Trace1/1
  Sum5/1 -> 速度制限/1
  Sum3/1 -> 左車輪速度要求/1
  右車輪回転角/1 -> Filter/1
  左車輪回転角/1 -> Filter1/1
  Constant3/1 -> 直進可否判定/3
  直進/1 -> 直進可否判定/1
  Logical Operator/1 -> 直進可否判定/2
  Sum2/1 -> 右車輪速度要求/1
  旋回/1 -> Sum2/2, Sum3/1
  Enable Line Trace1/1 -> Switch/3
  Sum4/1 -> Abs1/1
  Filter/1 -> Discrete Derivative2/1
  Filter1/1 -> Discrete Derivative3/1
  Discrete Derivative2/1 -> Sum7/1, Sum4/1
  Discrete Derivative3/1 -> Sum7/2, Sum4/2
  ゼロ割防止/1 -> Divide/2, 静止している( <  3cm/s)/1
  Abs1/1 -> Divide/1
  Divide/1 -> 旋回半径100cm以内?/1  "曲率計算"
  静止している( <  3cm/s)/1 -> Logical Operator/2
  旋回半径100cm以内?/1 -> Logical Operator/1
  Sum7/1 -> Abs2/1  "平均角速度"
  Abs2/1 -> ゼロ割防止/1

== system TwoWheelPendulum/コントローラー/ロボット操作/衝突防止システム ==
  Timer : Inport
  超音波センサー値 : Inport  Port=2
  右抑制前速度要求 : Inport  Port=3
  左抑制前速度要求 : Inport  Port=4
  enableCP : Inport  Port=5
  右側衝突防止演算 : Subsystem  TreatAsAtomicUnit=on
  左側衝突防止演算 : Subsystem  TreatAsAtomicUnit=on
  衝突防止アラーム生成 : Subsystem
  Vol_Freq : Outport
  右側速度要求 : Outport  Port=2
  左側速度要求 : Outport  Port=3
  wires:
  左側衝突防止演算/1(速度要求) -> 左側速度要求/1
  右抑制前速度要求/1 -> 右側衝突防止演算/2(抑制前速度要求)
  enableCP/1 -> 衝突防止アラーム生成/3(enableCP), 右側衝突防止演算/3(enableCP), 左側衝突防止演算/3(enableCP)
  超音波センサー値/1 -> 左側衝突防止演算/1(超音波センサー値), 右側衝突防止演算/1(超音波センサー値), 衝突防止アラーム生成/2(超音波センサー値)
  右側衝突防止演算/1(速度要求) -> 右側速度要求/1
  左抑制前速度要求/1 -> 左側衝突防止演算/2(抑制前速度要求)
  衝突防止アラーム生成/1(Vol_Freq) -> Vol_Freq/1
  Timer/1 -> 衝突防止アラーム生成/1(Timer)

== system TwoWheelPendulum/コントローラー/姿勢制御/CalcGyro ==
  Gyro : Inport
  Gain2 : Gain  Gain=0.99
  Gain4 : Gain  Gain=0.01
  Gyro初期値 : Constant  Value=0
  Sum1 : Sum  Inputs=-+|
  Sum2 : Sum  Inputs=++|
  Unit Delay External IC : simulink/Additional Math & Discrete/Additional Discrete/Unit Delay External IC  tsamp=-1
  GyroD : Outport
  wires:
  Gain4/1 -> Sum2/2
  Gyro初期値/1 -> Unit Delay External IC/2
  Gain2/1 -> Sum2/1
  Unit Delay External IC/1 -> Gain2/1
  Gyro/1 -> Sum1/2, Gain4/1
  Sum2/1 -> Unit Delay External IC/1, Sum1/1
  Sum1/1 -> GyroD/1

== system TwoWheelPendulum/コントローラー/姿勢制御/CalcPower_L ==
  Bat : Inport
  Req : Inport  Port=2
  Constant : Constant  Value=0.625  OutDataTypeStr=double  SampleTime=-1
  Coulomb & Viscous Friction : simulink/Discontinuities/Coulomb & Viscous Friction  offset=0  gain=1
  Gain1 : Gain  Gain=100
  Gain3 : Gain  Gain=0.001089
  Product1 : Product  Inputs=*/
  Sum4 : Sum  Inputs=|+-  SampleTime=1
  Pow : Outport
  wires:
  Constant/1 -> Sum4/2
  Gain3/1 -> Sum4/1
  Product1/1 -> Coulomb & Viscous Friction/1
  Req/1 -> Gain1/1
  Coulomb & Viscous Friction/1 -> Pow/1
  Sum4/1 -> Product1/2
  Gain1/1 -> Product1/1
  Bat/1 -> Gain3/1

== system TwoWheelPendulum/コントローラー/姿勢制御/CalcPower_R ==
  Bat : Inport
  Req : Inport  Port=2
  Constant : Constant  Value=0.625  OutDataTypeStr=double  SampleTime=-1
  Coulomb & Viscous Friction : simulink/Discontinuities/Coulomb & Viscous Friction  offset=0  gain=1
  Gain1 : Gain  Gain=100
  Gain3 : Gain  Gain=0.001089
  Product1 : Product  Inputs=*/
  Sum4 : Sum  Inputs=|+-  SampleTime=1
  Pow : Outport
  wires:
  Constant/1 -> Sum4/2
  Gain3/1 -> Sum4/1
  Product1/1 -> Coulomb & Viscous Friction/1
  Req/1 -> Gain1/1
  Coulomb & Viscous Friction/1 -> Pow/1
  Sum4/1 -> Product1/2
  Gain1/1 -> Product1/1
  Bat/1 -> Gain3/1

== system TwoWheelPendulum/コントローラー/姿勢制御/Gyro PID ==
  GyroD : Inport
  Reset : Inport  Port=2
  Discrete Gyro I : DiscreteIntegrator  ExternalReset=rising  InitialConditionSetting=State (most efficient)  SampleTime=-1  ICPrevOutput=DiscIntNeverNeededParam  ICPrevScaledInput=DiscIntNeverNeededParam
  Discrete Gyro P : DiscreteIntegrator  ExternalReset=rising  InitialConditionSetting=State (most efficient)  SampleTime=-1  ICPrevOutput=DiscIntNeverNeededParam  ICPrevScaledInput=DiscIntNeverNeededParam
  Gyro D : Gain  Gain=GD
  Gyro I : Gain  Gain=GI
  Gyro P : Gain  Gain=GP
  Sum4 : Sum  Inputs=3
  Req : Outport
  Theta : Outport  Port=2
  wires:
  Gyro I/1 -> Sum4/1
  Discrete Gyro I/1 -> Gyro I/1
  Gyro D/1 -> Sum4/3
  Gyro P/1 -> Sum4/2
  GyroD/1 -> Discrete Gyro P/1, Gyro D/1
  Reset/1 -> Discrete Gyro P/2, Discrete Gyro I/2
  Discrete Gyro P/1 -> Theta/1, Discrete Gyro I/1, Gyro P/1
  Sum4/1 -> Req/1

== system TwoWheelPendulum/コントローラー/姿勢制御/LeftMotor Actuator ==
  Req : Inport
  Reset : Inport  Port=2
  NoPower1 : Constant  Value=0
  Saturation : Saturate  UpperLimit=100  LowerLimit=-100
  Switch2 : Switch  Criteria=u2 ~= 0
  Pow : Outport
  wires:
  Req/1 -> Switch2/1
  Switch2/1 -> Saturation/1
  Reset/1 -> Switch2/2
  NoPower1/1 -> Switch2/3
  Saturation/1 -> Pow/1

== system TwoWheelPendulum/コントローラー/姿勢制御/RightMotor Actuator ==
  Req : Inport
  Reset : Inport  Port=2
  Gain5 : Gain  Gain=0.95
  NoPower : Constant  Value=0
  Saturation : Saturate  UpperLimit=100  LowerLimit=-100
  Switch2 : Switch  Criteria=u2 ~= 0
  Pow : Outport
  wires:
  Req/1 -> Gain5/1
  Gain5/1 -> Switch2/1
  Switch2/1 -> Saturation/1
  Reset/1 -> Switch2/2
  NoPower/1 -> Switch2/3
  Saturation/1 -> Pow/1

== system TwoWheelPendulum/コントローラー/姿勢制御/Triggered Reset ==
  Reset : Inport
  Delay : Delay  DelayLength=1
  Reset Trigger : Subsystem  TreatAsAtomicUnit=on
  Trigger : Outport
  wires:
  Delay/1 -> Reset Trigger/1(In)
  Reset Trigger/1(Out) -> Trigger/1, Delay/1
  Reset/1 -> Reset Trigger/Trigger

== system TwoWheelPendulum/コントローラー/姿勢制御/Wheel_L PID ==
  Reset : Inport
  Ang : Inport  Port=2
  Discrete Derivative1 : simulink/Discrete/Discrete Derivative  gainval=1.0  ICPrevScaledInput=0.0  InputProcessing=Inherited  OutMin=[]  OutMax=[]  OutDataType=fixdt(1, 16)  OutScaling=2^-10  DoSatur=off
  Discrete Gyro I1 : DiscreteIntegrator  ExternalReset=rising  InitialConditionSetting=State (most efficient)  SampleTime=-1  ICPrevOutput=DiscIntNeverNeededParam  ICPrevScaledInput=DiscIntNeverNeededParam
  Filter : DiscreteFilter  Numerator=[0.2]  Denominator=[1 -0.8]  ExternalReset=Rising
  Sum5 : Sum  Inputs=3
  Wheel D : Gain  Gain=WD
  Wheel I : Gain  Gain=WI
  Wheel P : Gain  Gain=WP
  Req : Outport
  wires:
  Ang/1 -> Wheel P/1, Filter/1, Discrete Gyro I1/1
  Filter/1 -> Discrete Derivative1/1
  Wheel I/1 -> Sum5/1
  Wheel D/1 -> Sum5/3
  Wheel P/1 -> Sum5/2
  Discrete Gyro I1/1 -> Wheel I/1
  Discrete Derivative1/1 -> Wheel D/1
  Reset/1 -> Filter/2, Discrete Gyro I1/2
  Sum5/1 -> Req/1

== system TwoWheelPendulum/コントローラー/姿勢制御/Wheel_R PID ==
  Reset : Inport
  Ang : Inport  Port=2
  Discrete Derivative1 : simulink/Discrete/Discrete Derivative  gainval=1.0  ICPrevScaledInput=0.0  InputProcessing=Inherited  OutMin=[]  OutMax=[]  OutDataType=fixdt(1, 16)  OutScaling=2^-10  DoSatur=off
  Discrete Gyro I1 : DiscreteIntegrator  ExternalReset=rising  InitialConditionSetting=State (most efficient)  SampleTime=-1  ICPrevOutput=DiscIntNeverNeededParam  ICPrevScaledInput=DiscIntNeverNeededParam
  Filter : DiscreteFilter  Numerator=[0.2]  Denominator=[1 -0.8]  ExternalReset=Rising
  Sum5 : Sum  Inputs=3
  Wheel D : Gain  Gain=WD
  Wheel I : Gain  Gain=WI
  Wheel P : Gain  Gain=WP
  Req : Outport
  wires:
  Ang/1 -> Wheel P/1, Filter/1, Discrete Gyro I1/1
  Filter/1 -> Discrete Derivative1/1
  Wheel I/1 -> Sum5/1
  Wheel D/1 -> Sum5/3
  Wheel P/1 -> Sum5/2
  Discrete Gyro I1/1 -> Wheel I/1
  Discrete Derivative1/1 -> Wheel D/1
  Reset/1 -> Filter/2, Discrete Gyro I1/2
  Sum5/1 -> Req/1

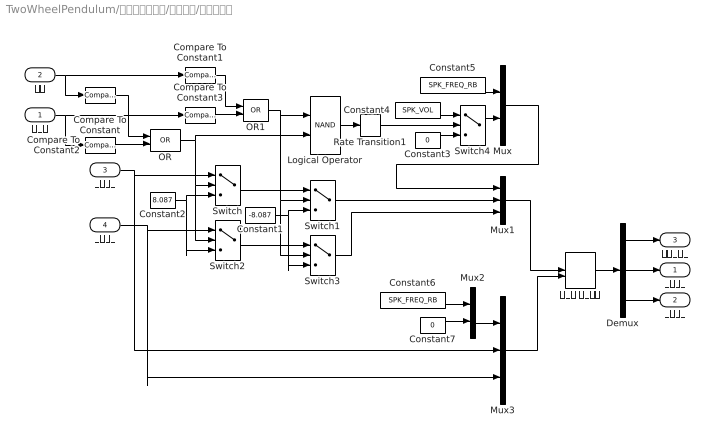
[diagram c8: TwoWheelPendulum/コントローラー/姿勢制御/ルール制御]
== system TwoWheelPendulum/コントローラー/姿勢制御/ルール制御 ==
  角速度 : Inport
  角度 : Inport  Port=2
  右要求値 : Inport  Port=3
  左要求値 : Inport  Port=4
  Compare To Constant : simulink/Logic and Bit Operations/Compare To Constant  relop=<  const=9  OutDataTypeStr=boolean
  Compare To Constant1 : simulink/Logic and Bit Operations/Compare To Constant  relop=>  const=-9  OutDataTypeStr=boolean
  Compare To Constant2 : simulink/Logic and Bit Operations/Compare To Constant  relop=<  const=50  OutDataTypeStr=boolean
  Compare To Constant3 : simulink/Logic and Bit Operations/Compare To Constant  relop=>  const=-50  OutDataTypeStr=boolean
  Constant1 : Constant  Value=-8.087
  Constant2 : Constant  Value=8.087
  Constant3 : Constant  Value=0
  Constant4 : Constant  Value=SPK_VOL
  Constant5 : Constant  Value=SPK_FREQ_RB
  Constant6 : Constant  Value=SPK_FREQ_RB
  Constant7 : Constant  Value=0
  Demux : Demux  Outputs=3
  Logical Operator : Logic  Operator=NAND  IconShape=distinctive  AllPortsSameDT=off  OutDataTypeStr=boolean
  Mux : Mux  Inputs=2
  Mux1 : Mux  Inputs=3
  Mux2 : Mux  Inputs=2
  Mux3 : Mux  Inputs=3
  OR : Logic  Operator=OR  IconShape=distinctive  AllPortsSameDT=off  OutDataTypeStr=boolean
  OR1 : Logic  Operator=OR  IconShape=distinctive  AllPortsSameDT=off  OutDataTypeStr=boolean
  Rate Transition1 : RateTransition  OutPortSampleTime=0.1
  Switch : Switch  Criteria=u2 ~= 0  Threshold=30
  Switch1 : Switch  Criteria=u2 ~= 0  Threshold=-30
  Switch2 : Switch  Criteria=u2 ~= 0  Threshold=30
  Switch3 : Switch  Criteria=u2 ~= 0  Threshold=-30
  Switch4 : Switch  Criteria=u2 ~= 0  Threshold=30
  ルール 有効無効 : ManualSwitch
  右補正値 : Outport
  左補正値 : Outport  Port=2
  スピーカー : Outport  Port=3
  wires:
  Switch3/1 -> Mux1/3
  Switch1/1 -> Mux1/2
  Constant2/1 -> Switch2/3, Switch/3
  右要求値/1 -> Mux3/2, Switch/1
  Switch/1 -> Switch1/1
  左要求値/1 -> Mux3/3, Switch2/1
  Constant1/1 -> Switch1/3, Switch3/3
  Switch2/1 -> Switch3/1
  OR/1 -> Switch2/2, Switch/2, Logical Operator/2
  OR1/1 -> Switch1/2, Switch3/2, Logical Operator/1
  Compare To Constant/1 -> OR/1
  Compare To Constant2/1 -> OR/2
  Compare To Constant1/1 -> OR1/1
  Compare To Constant3/1 -> OR1/2
  Logical Operator/1 -> Rate Transition1/1
  Demux/1 -> スピーカー/1
  Constant3/1 -> Switch4/3
  Constant4/1 -> Switch4/1
  Constant5/1 -> Mux/1
  Switch4/1 -> Mux/2
  角速度/1 -> Compare To Constant2/1, Compare To Constant3/1
  角度/1 -> Compare To Constant/1, Compare To Constant1/1
  Rate Transition1/1 -> Switch4/2
  Demux/2 -> 右補正値/1
  Demux/3 -> 左補正値/1
  Mux/1 -> Mux1/1
  Mux1/1 -> ルール 有効無効/1
  ルール 有効無効/1 -> Demux/1
  Constant6/1 -> Mux2/1
  Constant7/1 -> Mux2/2
  Mux2/1 -> Mux3/1
  Mux3/1 -> ルール 有効無効/2

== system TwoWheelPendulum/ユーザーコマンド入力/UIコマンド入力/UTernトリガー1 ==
  In1 : Inport
  Trigger : TriggerPort
  Out1 : Outport
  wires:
  In1/1 -> Out1/1

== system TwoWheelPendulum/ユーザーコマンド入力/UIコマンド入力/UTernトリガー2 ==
  In1 : Inport
  Trigger : TriggerPort
  Out1 : Outport
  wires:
  In1/1 -> Out1/1

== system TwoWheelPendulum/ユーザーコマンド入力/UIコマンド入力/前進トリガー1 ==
  In1 : Inport
  Trigger : TriggerPort
  Out1 : Outport
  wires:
  In1/1 -> Out1/1

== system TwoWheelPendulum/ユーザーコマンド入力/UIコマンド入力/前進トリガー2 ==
  In1 : Inport
  Trigger : TriggerPort
  Out1 : Outport
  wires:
  In1/1 -> Out1/1

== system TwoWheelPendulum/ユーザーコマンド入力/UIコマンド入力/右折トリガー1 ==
  In1 : Inport
  Trigger : TriggerPort
  Out1 : Outport
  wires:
  In1/1 -> Out1/1

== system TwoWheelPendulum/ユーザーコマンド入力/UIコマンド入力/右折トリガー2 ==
  In1 : Inport
  Trigger : TriggerPort
  Out1 : Outport
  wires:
  In1/1 -> Out1/1

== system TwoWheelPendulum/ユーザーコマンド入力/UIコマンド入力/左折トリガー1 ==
  In1 : Inport
  Trigger : TriggerPort
  Out1 : Outport
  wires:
  In1/1 -> Out1/1

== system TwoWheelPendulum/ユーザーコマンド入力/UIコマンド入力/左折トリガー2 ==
  In1 : Inport
  Trigger : TriggerPort
  Out1 : Outport
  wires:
  In1/1 -> Out1/1

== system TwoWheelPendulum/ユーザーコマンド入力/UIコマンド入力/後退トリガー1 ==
  In1 : Inport
  Trigger : TriggerPort
  Out1 : Outport
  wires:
  In1/1 -> Out1/1

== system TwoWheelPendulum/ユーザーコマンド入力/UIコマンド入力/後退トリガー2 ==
  In1 : Inport
  Trigger : TriggerPort
  Out1 : Outport
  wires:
  In1/1 -> Out1/1

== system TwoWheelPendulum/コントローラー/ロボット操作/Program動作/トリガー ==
  In : Inport
  Trigger : TriggerPort
  Out : Outport
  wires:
  In/1 -> Out/1

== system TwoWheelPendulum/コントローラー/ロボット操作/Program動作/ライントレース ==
  Light : Inport
  Bus Creator2 : BusCreator  Inputs=2
  CalcLight : Relay  OnSwitchValue=45  OffSwitchValue=44  OnOutputValue=LP  OffOutputValue=-LP
  Gain1 : Gain  Gain=-1
  Out : Outport
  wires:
  Bus Creator2/1 -> Out/1
  Gain1/1 -> Bus Creator2/2
  CalcLight/1 -> Bus Creator2/1, Gain1/1
  Light/1 -> CalcLight/1

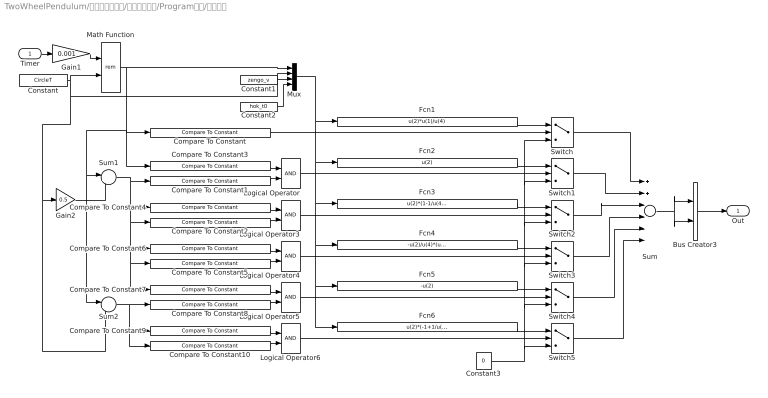
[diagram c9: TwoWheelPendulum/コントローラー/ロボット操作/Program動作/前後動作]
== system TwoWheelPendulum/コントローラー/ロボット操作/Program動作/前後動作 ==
  Timer : Inport
  Bus Creator3 : BusCreator  Inputs=2
  Compare To Constant : simulink/Logic and Bit Operations/Compare To Constant  relop=<=  const=hok_t0  OutDataTypeStr=boolean
  Compare To Constant1 : simulink/Logic and Bit Operations/Compare To Constant  relop=<=  const=-hok_t0  OutDataTypeStr=boolean
  Compare To Constant10 : simulink/Logic and Bit Operations/Compare To Constant  relop=<=  const=0  OutDataTypeStr=boolean
  Compare To Constant2 : simulink/Logic and Bit Operations/Compare To Constant  relop=<=  const=0  OutDataTypeStr=boolean
  Compare To Constant3 : simulink/Logic and Bit Operations/Compare To Constant  relop=>  const=hok_t0  OutDataTypeStr=boolean
  Compare To Constant4 : simulink/Logic and Bit Operations/Compare To Constant  relop=>  const=-hok_t0  OutDataTypeStr=boolean
  Compare To Constant5 : simulink/Logic and Bit Operations/Compare To Constant  relop=<=  const=hok_t0  OutDataTypeStr=boolean
  Compare To Constant6 : simulink/Logic and Bit Operations/Compare To Constant  relop=>  const=0  OutDataTypeStr=boolean
  Compare To Constant7 : simulink/Logic and Bit Operations/Compare To Constant  relop=>  const=hok_t0  OutDataTypeStr=boolean
  Compare To Constant8 : simulink/Logic and Bit Operations/Compare To Constant  relop=<=  const=-hok_t0  OutDataTypeStr=boolean
  Compare To Constant9 : simulink/Logic and Bit Operations/Compare To Constant  relop=>  const=-hok_t0  OutDataTypeStr=boolean
  Constant : Constant  Value=CircleT
  Constant1 : Constant  Value=zengo_v
  Constant2 : Constant  Value=hok_t0
  Constant3 : Constant  Value=0
  Fcn1 : Fcn  Expr=u(2)*u(1)/u(4)
  Fcn2 : Fcn  Expr=u(2)
  Fcn3 : Fcn  Expr=u(2)*(1-1/u(4)*(u(1)-u(3)/2+u(4)))
  Fcn4 : Fcn  Expr=-u(2)/u(4)*(u(1)-u(3)/2)
  Fcn5 : Fcn  Expr=-u(2)
  Fcn6 : Fcn  Expr=u(2)*(-1+1/u(4)*(u(1)-u(3)+u(4)))
  Gain1 : Gain  Gain=0.001
  Gain2 : Gain  Gain=0.5
  Logical Operator{,3..6} (5 alike) : Logic  AllPortsSameDT=off  OutDataTypeStr=boolean
  Math Function : Math  Operator=rem
  Mux : Mux
  Sum : Sum  Inputs=6
  Sum1 : Sum  Inputs=|+-
  Sum2 : Sum  Inputs=|+-
  Switch{,1..5} (6 alike) : Switch  Criteria=u2 > Threshold
  Out : Outport
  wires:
  Bus Creator3/1 -> Out/1
  Timer/1 -> Gain1/1
  Constant/1 -> Mux/3, Gain2/1, Sum2/2, Math Function/2
  Gain1/1 -> Math Function/1
  Math Function/1 -> Compare To Constant3/1, Compare To Constant/1, Sum2/1, Sum1/1, Mux/1
  Mux/1 -> Fcn6/1, Fcn5/1, Fcn4/1, Fcn3/1, Fcn2/1, Fcn1/1
  Constant1/1 -> Mux/2
  Compare To Constant/1 -> Switch/2
  Fcn1/1 -> Switch/1
  Fcn2/1 -> Switch1/1
  Switch1/1 -> Sum/2
  Fcn3/1 -> Switch2/1
  Constant3/1 -> Switch/3, Switch1/3, Switch2/3, Switch3/3, Switch4/3, Switch5/3
  Switch2/1 -> Sum/3
  Compare To Constant1/1 -> Logical Operator/2
  Logical Operator/1 -> Switch1/2
  Compare To Constant3/1 -> Logical Operator/1
  Compare To Constant2/1 -> Logical Operator3/2
  Compare To Constant4/1 -> Logical Operator3/1
  Logical Operator3/1 -> Switch2/2
  Fcn4/1 -> Switch3/1
  Compare To Constant5/1 -> Logical Operator4/2
  Logical Operator4/1 -> Switch3/2
  Compare To Constant6/1 -> Logical Operator4/1
  Switch3/1 -> Sum/4
  Compare To Constant7/1 -> Logical Operator5/1
  Compare To Constant8/1 -> Logical Operator5/2
  Fcn5/1 -> Switch4/1
  Logical Operator5/1 -> Switch4/2
  Switch4/1 -> Sum/5
  Compare To Constant9/1 -> Logical Operator6/1
  Compare To Constant10/1 -> Logical Operator6/2
  Fcn6/1 -> Switch5/1
  Logical Operator6/1 -> Switch5/2
  Switch5/1 -> Sum/6
  Sum/1 -> Bus Creator3/1, Bus Creator3/2
  Switch/1 -> Sum/1
  Gain2/1 -> Sum1/2
  Sum1/1 -> Compare To Constant4/1, Compare To Constant2/1, Compare To Constant6/1, Compare To Constant5/1, Compare To Constant7/1, Compare To Constant1/1
  Sum2/1 -> Compare To Constant9/1, Compare To Constant10/1, Compare To Constant8/1
  Constant2/1 -> Mux/4

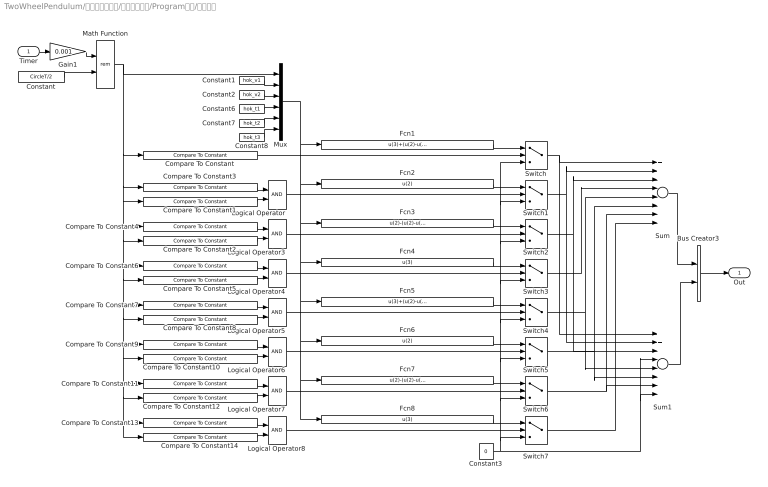
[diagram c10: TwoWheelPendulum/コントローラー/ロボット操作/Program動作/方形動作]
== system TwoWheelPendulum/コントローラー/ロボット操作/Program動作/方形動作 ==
  Timer : Inport
  Bus Creator3 : BusCreator  Inputs=2
  Compare To Constant : simulink/Logic and Bit Operations/Compare To Constant  relop=<=  const=hok_t0  OutDataTypeStr=boolean
  Compare To Constant1 : simulink/Logic and Bit Operations/Compare To Constant  relop=<=  const=hok_t0+hok_t2  OutDataTypeStr=boolean
  Compare To Constant10 : simulink/Logic and Bit Operations/Compare To Constant  relop=<=  const=3*hok_t0+hok_t1+hok_t2+hok_t3  OutDataTypeStr=boolean
  Compare To Constant11 : simulink/Logic and Bit Operations/Compare To Constant  relop=>  const=3*hok_t0+hok_t1+hok_t2+hok_t3  OutDataTypeStr=boolean
  Compare To Constant12 : simulink/Logic and Bit Operations/Compare To Constant  relop=<=  const=4*hok_t0+hok_t1+hok_t2+hok_t3  OutDataTypeStr=boolean
  Compare To Constant13 : simulink/Logic and Bit Operations/Compare To Constant  relop=>  const=4*hok_t0+hok_t1+hok_t2+hok_t3  OutDataTypeStr=boolean
  Compare To Constant14 : simulink/Logic and Bit Operations/Compare To Constant  relop=<=  const=4*hok_t0+2*hok_t1+hok_t2+hok_t3  OutDataTypeStr=boolean
  Compare To Constant2 : simulink/Logic and Bit Operations/Compare To Constant  relop=<=  const=2*hok_t0+hok_t2  OutDataTypeStr=boolean
  Compare To Constant3 : simulink/Logic and Bit Operations/Compare To Constant  relop=>  const=hok_t0  OutDataTypeStr=boolean
  Compare To Constant4 : simulink/Logic and Bit Operations/Compare To Constant  relop=>  const=hok_t0+hok_t2  OutDataTypeStr=boolean
  Compare To Constant5 : simulink/Logic and Bit Operations/Compare To Constant  relop=<=  const=2*hok_t0+hok_t1+hok_t2  OutDataTypeStr=boolean
  Compare To Constant6 : simulink/Logic and Bit Operations/Compare To Constant  relop=>  const=2*hok_t0+hok_t2  OutDataTypeStr=boolean
  Compare To Constant7 : simulink/Logic and Bit Operations/Compare To Constant  relop=>  const=2*hok_t0+hok_t1+hok_t2  OutDataTypeStr=boolean
  Compare To Constant8 : simulink/Logic and Bit Operations/Compare To Constant  relop=<=  const=3*hok_t0+hok_t1+hok_t2  OutDataTypeStr=boolean
  Compare To Constant9 : simulink/Logic and Bit Operations/Compare To Constant  relop=>  const=3*hok_t0+hok_t1+hok_t2  OutDataTypeStr=boolean
  Constant : Constant  Value=CircleT/2
  Constant1 : Constant  Value=hok_v1
  Constant2 : Constant  Value=hok_v2
  Constant3 : Constant  Value=0
  Constant6 : Constant  Value=hok_t1
  Constant7 : Constant  Value=hok_t2
  Constant8 : Constant  Value=hok_t3
  Fcn1 : Fcn  Expr=u(3)+(u(2)-u(3))/hok_t0*u(1)
  Fcn2 : Fcn  Expr=u(2)
  Fcn3 : Fcn  Expr=u(2)-(u(2)-u(3))/hok_t0*(u(1)-hok_t0-u(5))
  Fcn4 : Fcn  Expr=u(3)
  Fcn5 : Fcn  Expr=u(3)+(u(2)-u(3))/hok_t0*(u(1)-2*hok_t0-u(4)-u(5))
  Fcn6 : Fcn  Expr=u(2)
  Fcn7 : Fcn  Expr=u(2)-(u(2)-u(3))/hok_t0*(u(1)-3*hok_t0-u(4)-u(5)-u(6))
  Fcn8 : Fcn  Expr=u(3)
  Gain1 : Gain  Gain=0.001
  Logical Operator{,3..8} (7 alike) : Logic  AllPortsSameDT=off  OutDataTypeStr=boolean
  Math Function : Math  Operator=rem
  Mux : Mux  Inputs=6
  Sum : Sum  Inputs=8
  Sum1 : Sum  Inputs=8
  Switch{,1..7} (8 alike) : Switch  Criteria=u2 > Threshold
  Out : Outport
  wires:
  Bus Creator3/1 -> Out/1
  Timer/1 -> Gain1/1
  Constant/1 -> Math Function/2
  Gain1/1 -> Math Function/1
  Math Function/1 -> Compare To Constant13/1, Compare To Constant14/1, Compare To Constant12/1, Compare To Constant11/1, Compare To Constant10/1, Compare To Constant9/1, Compare To Constant8/1, Compare To Constant7/1, Compare To Constant5/1, Compare To Constant6/1, Compare To Constant2/1, Compare To Constant4/1, Compare To Constant1/1, Compare To Constant3/1, Compare To Constant/1, Mux/1
  Mux/1 -> Fcn8/1, Fcn7/1, Fcn6/1, Fcn5/1, Fcn4/1, Fcn3/1, Fcn2/1, Fcn1/1
  Constant2/1 -> Mux/3
  Constant1/1 -> Mux/2
  Compare To Constant/1 -> Switch/2
  Fcn1/1 -> Switch/1
  Switch/1 -> Sum1/1, Sum/1
  Fcn2/1 -> Switch1/1
  Switch1/1 -> Sum1/2, Sum/2
  Constant6/1 -> Mux/4
  Constant7/1 -> Mux/5
  Constant8/1 -> Mux/6
  Fcn3/1 -> Switch2/1
  Constant3/1 -> Switch/3, Switch1/3, Switch2/3, Switch3/3, Switch4/3, Switch5/3, Switch6/3, Switch7/3, Sum1/4, Sum1/8
  Switch2/1 -> Sum1/3, Sum/3
  Compare To Constant1/1 -> Logical Operator/2
  Logical Operator/1 -> Switch1/2
  Compare To Constant3/1 -> Logical Operator/1
  Compare To Constant2/1 -> Logical Operator3/2
  Compare To Constant4/1 -> Logical Operator3/1
  Logical Operator3/1 -> Switch2/2
  Fcn4/1 -> Switch3/1
  Compare To Constant5/1 -> Logical Operator4/2
  Logical Operator4/1 -> Switch3/2
  Compare To Constant6/1 -> Logical Operator4/1
  Switch3/1 -> Sum/4
  Compare To Constant7/1 -> Logical Operator5/1
  Compare To Constant8/1 -> Logical Operator5/2
  Fcn5/1 -> Switch4/1
  Logical Operator5/1 -> Switch4/2
  Switch4/1 -> Sum/5, Sum1/5
  Compare To Constant9/1 -> Logical Operator6/1
  Compare To Constant10/1 -> Logical Operator6/2
  Fcn6/1 -> Switch5/1
  Logical Operator6/1 -> Switch5/2
  Switch5/1 -> Sum/6, Sum1/6
  Compare To Constant11/1 -> Logical Operator7/1
  Compare To Constant12/1 -> Logical Operator7/2
  Fcn7/1 -> Switch6/1
  Logical Operator7/1 -> Switch6/2
  Switch6/1 -> Sum/7, Sum1/7
  Compare To Constant14/1 -> Logical Operator8/2
  Compare To Constant13/1 -> Logical Operator8/1
  Fcn8/1 -> Switch7/1
  Logical Operator8/1 -> Switch7/2
  Switch7/1 -> Sum/8
  Sum/1 -> Bus Creator3/1
  Sum1/1 -> Bus Creator3/2

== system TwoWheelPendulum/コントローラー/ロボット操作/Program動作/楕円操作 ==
  Timer : Inport
  Bus Creator3 : BusCreator  Inputs=2
  Constant : Constant  Value=LongR
  Constant1 : Constant  Value=ShortR
  Constant2 : Constant  Value=CircleT
  Fcn : Fcn  Expr=2*pi/u(4)*(((u(2)*sin(2*pi*u(1)/u(4)))^2+(u(3)*cos(2*pi*u(1)/u(4)))^2)^0.5+0.5*WheelBase*u(2)*u(3)/((u(2)*sin(2*pi*u(1)/u(4)))^2+(u(3)*cos(2*pi*u(1)/u(4)))^2))
  Fcn1 : Fcn  Expr=2*pi/u(4)*(((u(2)*sin(2*pi*u(1)/u(4)))^2+(u(3)*cos(2*pi*u(1)/u(4)))^2)^0.5-0.5*WheelBase*u(2)*u(3)/((u(2)*sin(2*pi*u(1)/u(4)))^2+(u(3)*cos(2*pi*u(1)/u(4)))^2))
  Gain : Gain  Gain=0.001
  Mux : Mux
  Out : Outport
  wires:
  Mux/1 -> Fcn/1, Fcn1/1
  Fcn1/1 -> Bus Creator3/2
  Timer/1 -> Gain/1
  Fcn/1 -> Bus Creator3/1
  Bus Creator3/1 -> Out/1
  Constant1/1 -> Mux/3
  Constant/1 -> Mux/2
  Gain/1 -> Mux/1
  Constant2/1 -> Mux/4

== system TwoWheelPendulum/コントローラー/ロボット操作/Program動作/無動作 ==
  Bus Creator4 : BusCreator  Inputs=2
  Constant2 : Constant  Value=0
  Out : Outport
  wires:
  Bus Creator4/1 -> Out/1
  Constant2/1 -> Bus Creator4/1, Bus Creator4/2
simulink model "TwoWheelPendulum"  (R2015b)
settings: Solver=ode45  StartTime=0.0  StopTime=200.0  RelTol=1e-3
PreLoadFcn:
  | UIPanel();
  | open_system('getLog.slx');
StartFcn:
  | set_param('getLog', 'SimulationCommand', 'start');
StopFcn:
  | set_param('getLog', 'SimulationCommand', 'stop');
  | execInit();
undefined symbols (not defined in the file or in its folder): CircleT, DiscIntNeverNeededParam, EnableCP, GD, GI, goBack, goBackP, goFor, goForP, goLeft, goLeftP, goRight, goRightP, goUTern, GP, hok_t0, hok_t1, hok_t2, hok_t3, hok_v1, hok_v2, LongR, LP, ProgramMode, ShortR, SPK_FREQ_RB, SPK_VOL, WD, WheelBase, WheelR, WI, WP, zengo_v
libraries: simulink x56, legoev3lib x18
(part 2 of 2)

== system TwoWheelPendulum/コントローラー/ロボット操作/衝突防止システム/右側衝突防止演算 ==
  超音波センサー値 : Inport
  抑制前速度要求 : Inport  Port=2
  enableCP : Inport  Port=3
  Constant : Constant  Value=0
  Constant2 : Constant  Value=0
  Discrete Filter : DiscreteFilter  Numerator=[0.4]  Denominator=[1 -0.6]
  Logical Operator1 : Logic  Operator=NOT  AllPortsSameDT=off  OutDataTypeStr=boolean
  Saturation : Saturate  UpperLimit=0  LowerLimit=-inf
  Sum2 : Sum  Inputs=|++
  Switch : Switch  Criteria=u2 ~= 0
  Switch1 : Switch  Threshold=10
  Switch2 : Switch  Threshold=23
  速度要求 : Outport
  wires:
  超音波センサー値/1 -> Switch1/2, Switch2/2
  Switch1/1 -> Sum2/2
  抑制前速度要求/1 -> Saturation/1, Switch2/1, Switch/1
  Constant/1 -> Switch1/3
  Constant2/1 -> Switch1/1
  Saturation/1 -> Sum2/1
  Sum2/1 -> Switch2/3
  enableCP/1 -> Logical Operator1/1
  Logical Operator1/1 -> Switch/2
  Switch/1 -> 速度要求/1
  Switch2/1 -> Discrete Filter/1
  Discrete Filter/1 -> Switch/3

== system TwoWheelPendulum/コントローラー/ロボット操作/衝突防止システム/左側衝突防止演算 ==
  超音波センサー値 : Inport
  抑制前速度要求 : Inport  Port=2
  enableCP : Inport  Port=3
  Constant : Constant  Value=0
  Constant2 : Constant  Value=0
  Discrete Filter : DiscreteFilter  Numerator=[0.4]  Denominator=[1 -0.6]
  Logical Operator1 : Logic  Operator=NOT  AllPortsSameDT=off  OutDataTypeStr=boolean
  Saturation : Saturate  UpperLimit=0  LowerLimit=-inf
  Sum2 : Sum  Inputs=|++
  Switch : Switch  Criteria=u2 ~= 0
  Switch1 : Switch  Threshold=10
  Switch2 : Switch  Threshold=23
  速度要求 : Outport
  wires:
  超音波センサー値/1 -> Switch1/2, Switch2/2
  Switch1/1 -> Sum2/2
  抑制前速度要求/1 -> Switch/1, Saturation/1, Switch2/1
  Constant/1 -> Switch1/3
  Constant2/1 -> Switch1/1
  Saturation/1 -> Sum2/1
  Sum2/1 -> Switch2/3
  enableCP/1 -> Logical Operator1/1
  Logical Operator1/1 -> Switch/2
  Switch/1 -> 速度要求/1
  Switch2/1 -> Discrete Filter/1
  Discrete Filter/1 -> Switch/3

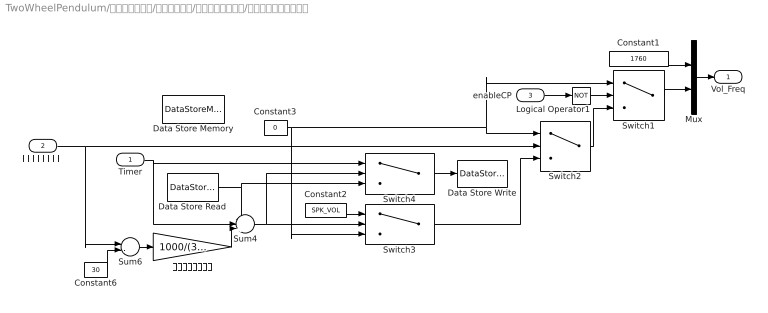
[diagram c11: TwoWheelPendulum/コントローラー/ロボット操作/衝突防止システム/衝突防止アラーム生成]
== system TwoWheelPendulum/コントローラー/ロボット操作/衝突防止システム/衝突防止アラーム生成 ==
  Timer : Inport
  超音波センサー値 : Inport  Port=2
  enableCP : Inport  Port=3
  Constant1 : Constant  Value=1760
  Constant2 : Constant  Value=SPK_VOL
  Constant3 : Constant  Value=0
  Constant6 : Constant  Value=30
  Data Store Memory : DataStoreMemory  DataStoreName=BeepTiming  ReadBeforeWriteMsg=warning  WriteAfterWriteMsg=warning  WriteAfterReadMsg=warning
  Data Store Read : DataStoreRead  DataStoreName=BeepTiming
  Data Store Write : DataStoreWrite  DataStoreName=BeepTiming
  Logical Operator1 : Logic  Operator=NOT  AllPortsSameDT=off  OutDataTypeStr=boolean
  Mux : Mux  Inputs=2
  Sum4 : Sum  Inputs=-++
  Sum6 : Sum  Inputs=|-+
  Switch1 : Switch  Criteria=u2 ~= 0  Threshold=50
  Switch2 : Switch  Threshold=30
  Switch3 : Switch  Threshold=1000
  Switch4 : Switch  Threshold=1000
  近づくと頻度上昇 : Gain  Gain=1000/(30-10)
  Vol_Freq : Outport
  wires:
  Switch2/1 -> Switch1/3
  Constant2/1 -> Switch3/1
  Switch3/1 -> Switch2/3
  近づくと頻度上昇/1 -> Sum4/3
  Constant6/1 -> Sum6/2
  Sum4/1 -> Switch3/2, Switch4/2
  Timer/1 -> Sum4/2, Switch4/1
  Sum6/1 -> 近づくと頻度上昇/1
  Data Store Read/1 -> Switch4/3, Sum4/1
  Constant3/1 -> Switch1/1, Switch2/1, Switch3/3
  Switch4/1 -> Data Store Write/1
  超音波センサー値/1 -> Sum6/1, Switch2/2
  enableCP/1 -> Logical Operator1/1
  Logical Operator1/1 -> Switch1/2
  Mux/1 -> Vol_Freq/1
  Switch1/1 -> Mux/2
  Constant1/1 -> Mux/1

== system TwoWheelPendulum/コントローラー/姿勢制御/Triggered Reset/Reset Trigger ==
  In : Inport
  Trigger : TriggerPort
  Logical Operator : Logic  Operator=NOT  AllPortsSameDT=off  OutDataTypeStr=boolean
  Out : Outport
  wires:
  In/1 -> Logical Operator/1
  Logical Operator/1 -> Out/1
